One B-rep face of a CAD part: STEP entity #1473.
In plain terms, the planar face has unit normal (-1, 0, 0).
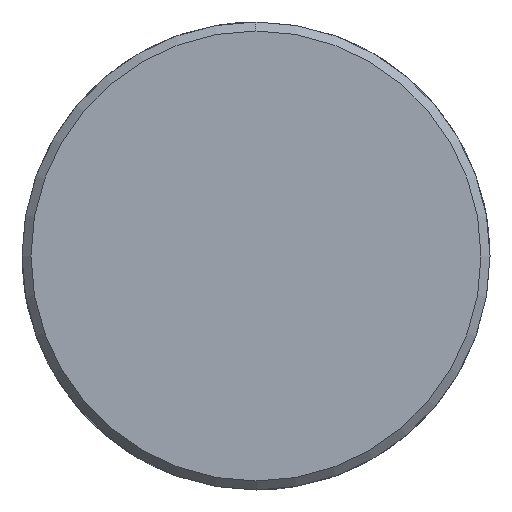
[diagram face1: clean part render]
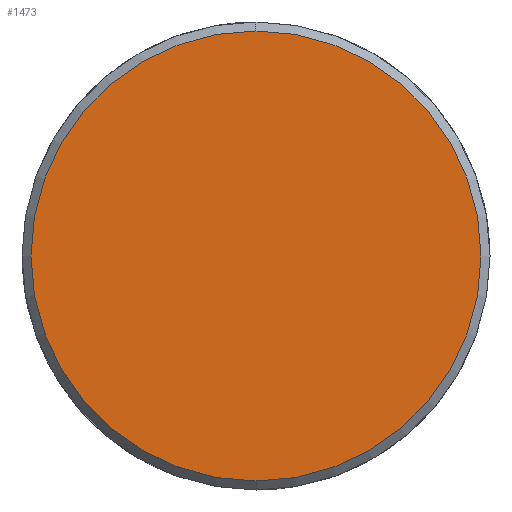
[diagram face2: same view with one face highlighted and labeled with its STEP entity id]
Its self-contained STEP definition (entity closure, numbers rounded to 3 decimals):
#1405=CARTESIAN_POINT('Vertex',(-8.,0.,-25.)) ;
#1408=CARTESIAN_POINT('Axis2P3D Location',(-8.,0.,0.)) ;
#1412=CARTESIAN_POINT('Vertex',(-8.,25.,0.)) ;
#1415=CARTESIAN_POINT('Axis2P3D Location',(-8.,0.,0.)) ;
#1419=CARTESIAN_POINT('Vertex',(-8.,0.,25.)) ;
#1441=CARTESIAN_POINT('Axis2P3D Location',(-8.,0.,0.)) ;
#1445=CARTESIAN_POINT('Vertex',(-8.,-25.,0.)) ;
#1448=CARTESIAN_POINT('Axis2P3D Location',(-8.,0.,0.)) ;
#1462=CARTESIAN_POINT('Axis2P3D Location',(-8.,0.,0.)) ;
#1409=DIRECTION('Axis2P3D Direction',(1.,0.,-0.)) ;
#1416=DIRECTION('Axis2P3D Direction',(1.,0.,-0.)) ;
#1442=DIRECTION('Axis2P3D Direction',(1.,0.,-0.)) ;
#1449=DIRECTION('Axis2P3D Direction',(1.,0.,-0.)) ;
#1463=DIRECTION('Axis2P3D Direction',(1.,0.,-0.)) ;
#1464=DIRECTION('Axis2P3D XDirection',(-0.,0.,-1.)) ;
#1410=AXIS2_PLACEMENT_3D('Circle Axis2P3D',#1408,#1409,$) ;
#1417=AXIS2_PLACEMENT_3D('Circle Axis2P3D',#1415,#1416,$) ;
#1443=AXIS2_PLACEMENT_3D('Circle Axis2P3D',#1441,#1442,$) ;
#1450=AXIS2_PLACEMENT_3D('Circle Axis2P3D',#1448,#1449,$) ;
#1465=AXIS2_PLACEMENT_3D('Plane Axis2P3D',#1462,#1463,#1464) ;
#1468=ORIENTED_EDGE('',*,*,#1414,.F.) ;
#1469=ORIENTED_EDGE('',*,*,#1452,.F.) ;
#1470=ORIENTED_EDGE('',*,*,#1447,.F.) ;
#1471=ORIENTED_EDGE('',*,*,#1421,.F.) ;
#1473=ADVANCED_FACE('351-40X76X220',(#1472),#1466,.F.) ;
#1411=CIRCLE('generated circle',#1410,25.) ;
#1418=CIRCLE('generated circle',#1417,25.) ;
#1444=CIRCLE('generated circle',#1443,25.) ;
#1451=CIRCLE('generated circle',#1450,25.) ;
#1414=EDGE_CURVE('',#1406,#1413,#1411,.T.) ;
#1421=EDGE_CURVE('',#1413,#1420,#1418,.T.) ;
#1447=EDGE_CURVE('',#1420,#1446,#1444,.T.) ;
#1452=EDGE_CURVE('',#1446,#1406,#1451,.T.) ;
#1467=EDGE_LOOP('',(#1468,#1469,#1470,#1471)) ;
#1472=FACE_OUTER_BOUND('',#1467,.T.) ;
#1466=PLANE('Plane',#1465) ;
#1406=VERTEX_POINT('',#1405) ;
#1413=VERTEX_POINT('',#1412) ;
#1420=VERTEX_POINT('',#1419) ;
#1446=VERTEX_POINT('',#1445) ;
